VERSION 5.7 ;
  NOWIREEXTENSIONATPIN ON ;
  DIVIDERCHAR "/" ;
  BUSBITCHARS "[]" ;
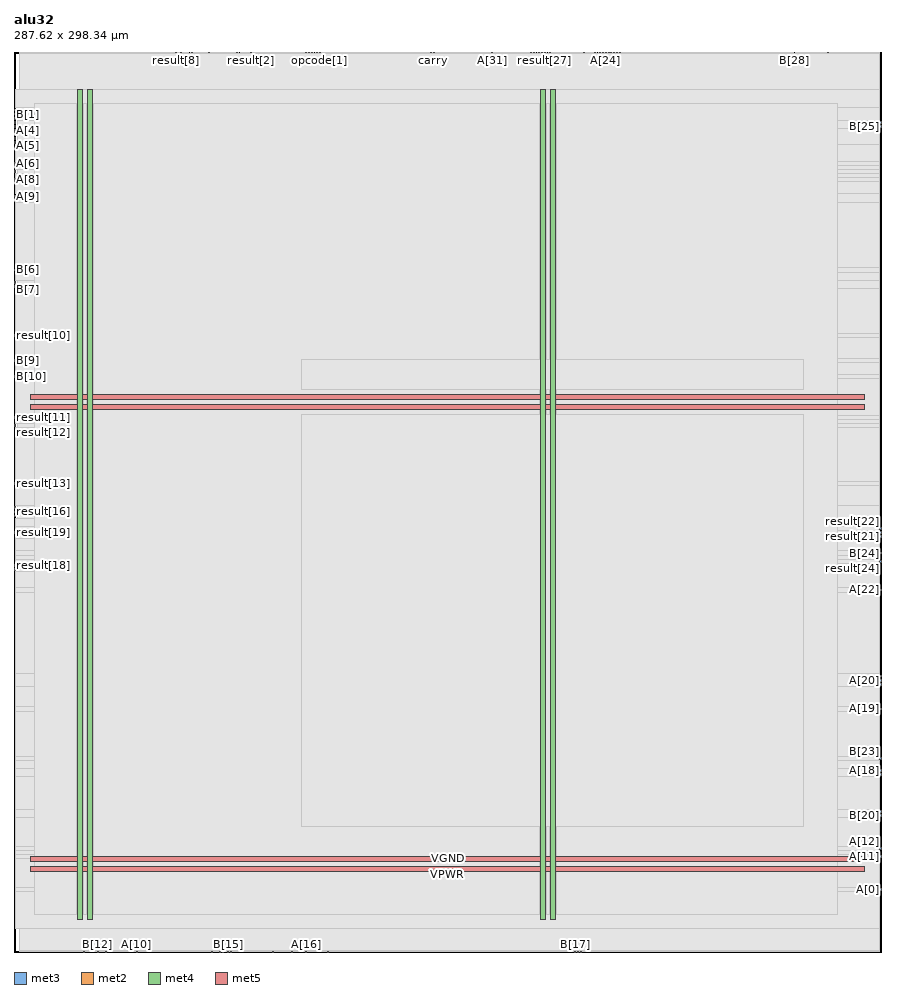
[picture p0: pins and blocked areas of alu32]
MACRO alu32
  CLASS BLOCK ;
  FOREIGN alu32 ;
  ORIGIN 0.000 0.000 ;
  SIZE 287.620 BY 298.340 ;
  PIN A[0]
    DIRECTION INPUT ;
    USE SIGNAL ;
    ANTENNAGATEAREA 0.213000 ;
    PORT
      LAYER met3 ;
        RECT 287.020 20.440 287.620 21.040 ;
    END
  END A[0]
  PIN A[10]
    DIRECTION INPUT ;
    USE SIGNAL ;
    ANTENNAGATEAREA 0.213000 ;
    PORT
      LAYER met2 ;
        RECT 40.570 0.000 40.850 0.280 ;
    END
  END A[10]
  PIN A[11]
    DIRECTION INPUT ;
    USE SIGNAL ;
    ANTENNAGATEAREA 0.247500 ;
    PORT
      LAYER met3 ;
        RECT 287.020 31.320 287.620 31.920 ;
    END
  END A[11]
  PIN A[12]
    DIRECTION INPUT ;
    USE SIGNAL ;
    ANTENNAGATEAREA 0.213000 ;
    PORT
      LAYER met3 ;
        RECT 287.020 34.040 287.620 34.640 ;
    END
  END A[12]
  PIN A[13]
    DIRECTION INPUT ;
    USE SIGNAL ;
    ANTENNAGATEAREA 0.213000 ;
    PORT
      LAYER met2 ;
        RECT 65.410 0.000 65.690 0.280 ;
    END
  END A[13]
  PIN A[14]
    DIRECTION INPUT ;
    USE SIGNAL ;
    ANTENNAGATEAREA 0.159000 ;
    PORT
      LAYER met2 ;
        RECT 68.170 0.000 68.450 0.280 ;
    END
  END A[14]
  PIN A[15]
    DIRECTION INPUT ;
    USE SIGNAL ;
    ANTENNAGATEAREA 0.213000 ;
    PORT
      LAYER met2 ;
        RECT 71.850 0.000 72.130 0.280 ;
    END
  END A[15]
  PIN A[16]
    DIRECTION INPUT ;
    USE SIGNAL ;
    ANTENNAGATEAREA 0.213000 ;
    PORT
      LAYER met2 ;
        RECT 96.690 0.000 96.970 0.280 ;
    END
  END A[16]
  PIN A[17]
    DIRECTION INPUT ;
    USE SIGNAL ;
    ANTENNAGATEAREA 0.196500 ;
    PORT
      LAYER met2 ;
        RECT 85.650 0.000 85.930 0.280 ;
    END
  END A[17]
  PIN A[18]
    DIRECTION INPUT ;
    USE SIGNAL ;
    ANTENNAGATEAREA 0.213000 ;
    PORT
      LAYER met3 ;
        RECT 287.020 59.880 287.620 60.480 ;
    END
  END A[18]
  PIN A[19]
    DIRECTION INPUT ;
    USE SIGNAL ;
    ANTENNAGATEAREA 0.213000 ;
    PORT
      LAYER met3 ;
        RECT 287.020 80.280 287.620 80.880 ;
    END
  END A[19]
  PIN A[1]
    DIRECTION INPUT ;
    USE SIGNAL ;
    ANTENNAGATEAREA 0.495000 ;
    PORT
      LAYER met3 ;
        RECT 0.000 278.840 0.600 279.440 ;
    END
  END A[1]
  PIN A[20]
    DIRECTION INPUT ;
    USE SIGNAL ;
    ANTENNAGATEAREA 0.213000 ;
    PORT
      LAYER met3 ;
        RECT 287.020 89.800 287.620 90.400 ;
    END
  END A[20]
  PIN A[21]
    DIRECTION INPUT ;
    USE SIGNAL ;
    ANTENNAGATEAREA 0.213000 ;
    PORT
      LAYER met3 ;
        RECT 287.020 88.440 287.620 89.040 ;
    END
  END A[21]
  PIN A[22]
    DIRECTION INPUT ;
    USE SIGNAL ;
    ANTENNAGATEAREA 0.213000 ;
    PORT
      LAYER met3 ;
        RECT 287.020 119.720 287.620 120.320 ;
    END
  END A[22]
  PIN A[23]
    DIRECTION INPUT ;
    USE SIGNAL ;
    ANTENNAGATEAREA 0.213000 ;
    PORT
      LAYER met3 ;
        RECT 287.020 91.160 287.620 91.760 ;
    END
  END A[23]
  PIN A[24]
    DIRECTION INPUT ;
    USE SIGNAL ;
    ANTENNAGATEAREA 0.213000 ;
    PORT
      LAYER met2 ;
        RECT 196.050 298.060 196.330 298.340 ;
    END
  END A[24]
  PIN A[25]
    DIRECTION INPUT ;
    USE SIGNAL ;
    ANTENNAGATEAREA 0.213000 ;
    PORT
      LAYER met2 ;
        RECT 195.130 298.060 195.410 298.340 ;
    END
  END A[25]
  PIN A[26]
    DIRECTION INPUT ;
    USE SIGNAL ;
    ANTENNAGATEAREA 0.213000 ;
    PORT
      LAYER met2 ;
        RECT 197.890 298.060 198.170 298.340 ;
    END
  END A[26]
  PIN A[27]
    DIRECTION INPUT ;
    USE SIGNAL ;
    ANTENNAGATEAREA 0.213000 ;
    PORT
      LAYER met2 ;
        RECT 198.810 298.060 199.090 298.340 ;
    END
  END A[27]
  PIN A[28]
    DIRECTION INPUT ;
    USE SIGNAL ;
    ANTENNAGATEAREA 0.213000 ;
    PORT
      LAYER met2 ;
        RECT 199.730 298.060 200.010 298.340 ;
    END
  END A[28]
  PIN A[29]
    DIRECTION INPUT ;
    USE SIGNAL ;
    ANTENNAGATEAREA 0.213000 ;
    PORT
      LAYER met2 ;
        RECT 200.650 298.060 200.930 298.340 ;
    END
  END A[29]
  PIN A[2]
    DIRECTION INPUT ;
    USE SIGNAL ;
    ANTENNAGATEAREA 0.247500 ;
    PORT
      LAYER met3 ;
        RECT 0.000 276.120 0.600 276.720 ;
    END
  END A[2]
  PIN A[30]
    DIRECTION INPUT ;
    USE SIGNAL ;
    ANTENNAGATEAREA 0.196500 ;
    PORT
      LAYER met2 ;
        RECT 196.970 298.060 197.250 298.340 ;
    END
  END A[30]
  PIN A[31]
    DIRECTION INPUT ;
    USE SIGNAL ;
    ANTENNAGATEAREA 0.213000 ;
    PORT
      LAYER met2 ;
        RECT 158.330 298.060 158.610 298.340 ;
    END
  END A[31]
  PIN A[3]
    DIRECTION INPUT ;
    USE SIGNAL ;
    ANTENNAGATEAREA 0.213000 ;
    PORT
      LAYER met3 ;
        RECT 0.000 274.760 0.600 275.360 ;
    END
  END A[3]
  PIN A[4]
    DIRECTION INPUT ;
    USE SIGNAL ;
    ANTENNAGATEAREA 0.213000 ;
    PORT
      LAYER met3 ;
        RECT 0.000 272.040 0.600 272.640 ;
    END
  END A[4]
  PIN A[5]
    DIRECTION INPUT ;
    USE SIGNAL ;
    ANTENNAGATEAREA 0.247500 ;
    PORT
      LAYER met3 ;
        RECT 0.000 269.320 0.600 269.920 ;
    END
  END A[5]
  PIN A[6]
    DIRECTION INPUT ;
    USE SIGNAL ;
    ANTENNAGATEAREA 0.247500 ;
    PORT
      LAYER met3 ;
        RECT 0.000 261.160 0.600 261.760 ;
    END
  END A[6]
  PIN A[7]
    DIRECTION INPUT ;
    USE SIGNAL ;
    ANTENNAGATEAREA 0.213000 ;
    PORT
      LAYER met3 ;
        RECT 0.000 258.440 0.600 259.040 ;
    END
  END A[7]
  PIN A[8]
    DIRECTION INPUT ;
    USE SIGNAL ;
    ANTENNAGATEAREA 0.213000 ;
    PORT
      LAYER met3 ;
        RECT 0.000 255.720 0.600 256.320 ;
    END
  END A[8]
  PIN A[9]
    DIRECTION INPUT ;
    USE SIGNAL ;
    ANTENNAGATEAREA 0.213000 ;
    PORT
      LAYER met3 ;
        RECT 0.000 250.280 0.600 250.880 ;
    END
  END A[9]
  PIN B[0]
    DIRECTION INPUT ;
    USE SIGNAL ;
    ANTENNAGATEAREA 0.126000 ;
    PORT
      LAYER met2 ;
        RECT 194.210 298.060 194.490 298.340 ;
    END
  END B[0]
  PIN B[10]
    DIRECTION INPUT ;
    USE SIGNAL ;
    ANTENNAGATEAREA 0.213000 ;
    PORT
      LAYER met3 ;
        RECT 0.000 190.440 0.600 191.040 ;
    END
  END B[10]
  PIN B[11]
    DIRECTION INPUT ;
    USE SIGNAL ;
    ANTENNAGATEAREA 0.126000 ;
    PORT
      LAYER met2 ;
        RECT 23.090 0.000 23.370 0.280 ;
    END
  END B[11]
  PIN B[12]
    DIRECTION INPUT ;
    USE SIGNAL ;
    ANTENNAGATEAREA 0.247500 ;
    PORT
      LAYER met2 ;
        RECT 27.690 0.000 27.970 0.280 ;
    END
  END B[12]
  PIN B[13]
    DIRECTION INPUT ;
    USE SIGNAL ;
    ANTENNAGATEAREA 0.213000 ;
    PORT
      LAYER met2 ;
        RECT 30.450 0.000 30.730 0.280 ;
    END
  END B[13]
  PIN B[14]
    DIRECTION INPUT ;
    USE SIGNAL ;
    ANTENNAGATEAREA 0.213000 ;
    PORT
      LAYER met2 ;
        RECT 69.090 0.000 69.370 0.280 ;
    END
  END B[14]
  PIN B[15]
    DIRECTION INPUT ;
    USE SIGNAL ;
    ANTENNAGATEAREA 0.213000 ;
    PORT
      LAYER met2 ;
        RECT 70.930 0.000 71.210 0.280 ;
    END
  END B[15]
  PIN B[16]
    DIRECTION INPUT ;
    USE SIGNAL ;
    ANTENNAGATEAREA 0.213000 ;
    PORT
      LAYER met2 ;
        RECT 92.090 0.000 92.370 0.280 ;
    END
  END B[16]
  PIN B[17]
    DIRECTION INPUT ;
    USE SIGNAL ;
    ANTENNAGATEAREA 0.126000 ;
    PORT
      LAYER met2 ;
        RECT 185.930 0.000 186.210 0.280 ;
    END
  END B[17]
  PIN B[18]
    DIRECTION INPUT ;
    USE SIGNAL ;
    ANTENNAGATEAREA 0.126000 ;
    PORT
      LAYER met2 ;
        RECT 186.850 0.000 187.130 0.280 ;
    END
  END B[18]
  PIN B[19]
    DIRECTION INPUT ;
    USE SIGNAL ;
    ANTENNAGATEAREA 0.213000 ;
    PORT
      LAYER met2 ;
        RECT 187.770 0.000 188.050 0.280 ;
    END
  END B[19]
  PIN B[1]
    DIRECTION INPUT ;
    USE SIGNAL ;
    ANTENNAGATEAREA 0.213000 ;
    PORT
      LAYER met3 ;
        RECT 0.000 277.480 0.600 278.080 ;
    END
  END B[1]
  PIN B[20]
    DIRECTION INPUT ;
    USE SIGNAL ;
    ANTENNAGATEAREA 0.126000 ;
    PORT
      LAYER met3 ;
        RECT 287.020 44.920 287.620 45.520 ;
    END
  END B[20]
  PIN B[21]
    DIRECTION INPUT ;
    USE SIGNAL ;
    ANTENNAGATEAREA 0.126000 ;
    PORT
      LAYER met3 ;
        RECT 287.020 46.280 287.620 46.880 ;
    END
  END B[21]
  PIN B[22]
    DIRECTION INPUT ;
    USE SIGNAL ;
    ANTENNAGATEAREA 0.213000 ;
    PORT
      LAYER met3 ;
        RECT 287.020 58.520 287.620 59.120 ;
    END
  END B[22]
  PIN B[23]
    DIRECTION INPUT ;
    USE SIGNAL ;
    ANTENNAGATEAREA 0.213000 ;
    PORT
      LAYER met3 ;
        RECT 287.020 63.960 287.620 64.560 ;
    END
  END B[23]
  PIN B[24]
    DIRECTION INPUT ;
    USE SIGNAL ;
    ANTENNAGATEAREA 0.213000 ;
    PORT
      LAYER met3 ;
        RECT 287.020 131.960 287.620 132.560 ;
    END
  END B[24]
  PIN B[25]
    DIRECTION INPUT ;
    USE SIGNAL ;
    ANTENNAGATEAREA 0.213000 ;
    PORT
      LAYER met3 ;
        RECT 287.020 273.400 287.620 274.000 ;
    END
  END B[25]
  PIN B[26]
    DIRECTION INPUT ;
    USE SIGNAL ;
    ANTENNAGATEAREA 0.213000 ;
    PORT
      LAYER met3 ;
        RECT 287.020 274.760 287.620 275.360 ;
    END
  END B[26]
  PIN B[27]
    DIRECTION INPUT ;
    USE SIGNAL ;
    ANTENNAGATEAREA 0.213000 ;
    PORT
      LAYER met2 ;
        RECT 269.650 298.060 269.930 298.340 ;
    END
  END B[27]
  PIN B[28]
    DIRECTION INPUT ;
    USE SIGNAL ;
    ANTENNAGATEAREA 0.196500 ;
    PORT
      LAYER met2 ;
        RECT 258.610 298.060 258.890 298.340 ;
    END
  END B[28]
  PIN B[29]
    DIRECTION INPUT ;
    USE SIGNAL ;
    ANTENNAGATEAREA 0.213000 ;
    PORT
      LAYER met2 ;
        RECT 193.290 298.060 193.570 298.340 ;
    END
  END B[29]
  PIN B[2]
    DIRECTION INPUT ;
    USE SIGNAL ;
    ANTENNAGATEAREA 0.213000 ;
    PORT
      LAYER met3 ;
        RECT 0.000 273.400 0.600 274.000 ;
    END
  END B[2]
  PIN B[30]
    DIRECTION INPUT ;
    USE SIGNAL ;
    ANTENNAGATEAREA 0.213000 ;
    PORT
      LAYER met2 ;
        RECT 192.370 298.060 192.650 298.340 ;
    END
  END B[30]
  PIN B[31]
    DIRECTION INPUT ;
    USE SIGNAL ;
    ANTENNAGATEAREA 0.213000 ;
    PORT
      LAYER met2 ;
        RECT 188.690 298.060 188.970 298.340 ;
    END
  END B[31]
  PIN B[3]
    DIRECTION INPUT ;
    USE SIGNAL ;
    ANTENNAGATEAREA 0.213000 ;
    PORT
      LAYER met3 ;
        RECT 0.000 270.680 0.600 271.280 ;
    END
  END B[3]
  PIN B[4]
    DIRECTION INPUT ;
    USE SIGNAL ;
    ANTENNAGATEAREA 0.213000 ;
    PORT
      LAYER met3 ;
        RECT 0.000 267.960 0.600 268.560 ;
    END
  END B[4]
  PIN B[5]
    DIRECTION INPUT ;
    USE SIGNAL ;
    ANTENNAGATEAREA 0.159000 ;
    PORT
      LAYER met3 ;
        RECT 0.000 248.920 0.600 249.520 ;
    END
  END B[5]
  PIN B[6]
    DIRECTION INPUT ;
    USE SIGNAL ;
    ANTENNAGATEAREA 0.247500 ;
    PORT
      LAYER met3 ;
        RECT 0.000 225.800 0.600 226.400 ;
    END
  END B[6]
  PIN B[7]
    DIRECTION INPUT ;
    USE SIGNAL ;
    ANTENNAGATEAREA 0.495000 ;
    PORT
      LAYER met3 ;
        RECT 0.000 221.720 0.600 222.320 ;
    END
  END B[7]
  PIN B[8]
    DIRECTION INPUT ;
    USE SIGNAL ;
    ANTENNAGATEAREA 0.159000 ;
    PORT
      LAYER met3 ;
        RECT 0.000 220.360 0.600 220.960 ;
    END
  END B[8]
  PIN B[9]
    DIRECTION INPUT ;
    USE SIGNAL ;
    ANTENNAGATEAREA 0.213000 ;
    PORT
      LAYER met3 ;
        RECT 0.000 195.880 0.600 196.480 ;
    END
  END B[9]
  PIN VGND
    DIRECTION INOUT ;
    USE GROUND ;
    PORT
      LAYER met4 ;
        RECT 24.340 10.640 25.940 285.840 ;
    END
    PORT
      LAYER met4 ;
        RECT 177.940 10.640 179.540 285.840 ;
    END
    PORT
      LAYER met5 ;
        RECT 5.520 30.030 281.980 31.630 ;
    END
    PORT
      LAYER met5 ;
        RECT 5.520 183.210 281.980 184.810 ;
    END
  END VGND
  PIN VPWR
    DIRECTION INOUT ;
    USE POWER ;
    PORT
      LAYER met4 ;
        RECT 21.040 10.640 22.640 285.840 ;
    END
    PORT
      LAYER met4 ;
        RECT 174.640 10.640 176.240 285.840 ;
    END
    PORT
      LAYER met5 ;
        RECT 5.520 26.730 281.980 28.330 ;
    END
    PORT
      LAYER met5 ;
        RECT 5.520 179.910 281.980 181.510 ;
    END
  END VPWR
  PIN carry
    DIRECTION OUTPUT ;
    USE SIGNAL ;
    ANTENNAGATEAREA 0.126000 ;
    ANTENNADIFFAREA 0.429000 ;
    PORT
      LAYER met2 ;
        RECT 139.010 298.060 139.290 298.340 ;
    END
  END carry
  PIN opcode[0]
    DIRECTION INPUT ;
    USE SIGNAL ;
    ANTENNAGATEAREA 0.213000 ;
    PORT
      LAYER met2 ;
        RECT 98.530 298.060 98.810 298.340 ;
    END
  END opcode[0]
  PIN opcode[1]
    DIRECTION INPUT ;
    USE SIGNAL ;
    ANTENNAGATEAREA 0.213000 ;
    PORT
      LAYER met2 ;
        RECT 101.290 298.060 101.570 298.340 ;
    END
  END opcode[1]
  PIN opcode[2]
    DIRECTION INPUT ;
    USE SIGNAL ;
    ANTENNAGATEAREA 0.213000 ;
    PORT
      LAYER met2 ;
        RECT 99.450 298.060 99.730 298.340 ;
    END
  END opcode[2]
  PIN opcode[3]
    DIRECTION INPUT ;
    USE SIGNAL ;
    ANTENNAGATEAREA 0.213000 ;
    PORT
      LAYER met2 ;
        RECT 100.370 298.060 100.650 298.340 ;
    END
  END opcode[3]
  PIN overflow
    DIRECTION OUTPUT ;
    USE SIGNAL ;
    ANTENNADIFFAREA 1.782000 ;
    PORT
      LAYER met2 ;
        RECT 138.090 298.060 138.370 298.340 ;
    END
  END overflow
  PIN result[0]
    DIRECTION OUTPUT ;
    USE SIGNAL ;
    ANTENNAGATEAREA 0.126000 ;
    ANTENNADIFFAREA 0.429000 ;
    PORT
      LAYER met2 ;
        RECT 97.610 298.060 97.890 298.340 ;
    END
  END result[0]
  PIN result[10]
    DIRECTION OUTPUT ;
    USE SIGNAL ;
    ANTENNADIFFAREA 0.383400 ;
    PORT
      LAYER met3 ;
        RECT 0.000 204.040 0.600 204.640 ;
    END
  END result[10]
  PIN result[11]
    DIRECTION OUTPUT ;
    USE SIGNAL ;
    ANTENNADIFFAREA 0.383400 ;
    PORT
      LAYER met3 ;
        RECT 0.000 176.840 0.600 177.440 ;
    END
  END result[11]
  PIN result[12]
    DIRECTION OUTPUT ;
    USE SIGNAL ;
    ANTENNAGATEAREA 0.126000 ;
    ANTENNADIFFAREA 0.429000 ;
    PORT
      LAYER met3 ;
        RECT 0.000 174.120 0.600 174.720 ;
    END
  END result[12]
  PIN result[13]
    DIRECTION OUTPUT ;
    USE SIGNAL ;
    ANTENNAGATEAREA 0.126000 ;
    ANTENNADIFFAREA 0.429000 ;
    PORT
      LAYER met3 ;
        RECT 0.000 155.080 0.600 155.680 ;
    END
  END result[13]
  PIN result[14]
    DIRECTION OUTPUT ;
    USE SIGNAL ;
    ANTENNADIFFAREA 0.383400 ;
    PORT
      LAYER met3 ;
        RECT 0.000 146.920 0.600 147.520 ;
    END
  END result[14]
  PIN result[15]
    DIRECTION OUTPUT ;
    USE SIGNAL ;
    ANTENNADIFFAREA 0.383400 ;
    PORT
      LAYER met3 ;
        RECT 0.000 144.200 0.600 144.800 ;
    END
  END result[15]
  PIN result[16]
    DIRECTION OUTPUT ;
    USE SIGNAL ;
    ANTENNAGATEAREA 0.126000 ;
    ANTENNADIFFAREA 0.429000 ;
    PORT
      LAYER met3 ;
        RECT 0.000 145.560 0.600 146.160 ;
    END
  END result[16]
  PIN result[17]
    DIRECTION OUTPUT ;
    USE SIGNAL ;
    ANTENNAGATEAREA 0.126000 ;
    ANTENNADIFFAREA 0.429000 ;
    PORT
      LAYER met2 ;
        RECT 104.050 0.000 104.330 0.280 ;
    END
  END result[17]
  PIN result[18]
    DIRECTION OUTPUT ;
    USE SIGNAL ;
    ANTENNAGATEAREA 0.126000 ;
    ANTENNADIFFAREA 0.429000 ;
    PORT
      LAYER met3 ;
        RECT 0.000 127.880 0.600 128.480 ;
    END
  END result[18]
  PIN result[19]
    DIRECTION OUTPUT ;
    USE SIGNAL ;
    ANTENNADIFFAREA 0.383400 ;
    PORT
      LAYER met3 ;
        RECT 0.000 138.760 0.600 139.360 ;
    END
  END result[19]
  PIN result[1]
    DIRECTION OUTPUT ;
    USE SIGNAL ;
    ANTENNADIFFAREA 0.702900 ;
    PORT
      LAYER met2 ;
        RECT 96.690 298.060 96.970 298.340 ;
    END
  END result[1]
  PIN result[20]
    DIRECTION OUTPUT ;
    USE SIGNAL ;
    ANTENNADIFFAREA 0.891000 ;
    PORT
      LAYER met3 ;
        RECT 0.000 126.520 0.600 127.120 ;
    END
  END result[20]
  PIN result[21]
    DIRECTION OUTPUT ;
    USE SIGNAL ;
    ANTENNADIFFAREA 0.383400 ;
    PORT
      LAYER met3 ;
        RECT 287.020 137.400 287.620 138.000 ;
    END
  END result[21]
  PIN result[22]
    DIRECTION OUTPUT ;
    USE SIGNAL ;
    ANTENNADIFFAREA 1.782000 ;
    PORT
      LAYER met3 ;
        RECT 287.020 140.120 287.620 140.720 ;
    END
  END result[22]
  PIN result[23]
    DIRECTION OUTPUT ;
    USE SIGNAL ;
    ANTENNAGATEAREA 0.126000 ;
    ANTENNADIFFAREA 0.429000 ;
    PORT
      LAYER met3 ;
        RECT 287.020 138.760 287.620 139.360 ;
    END
  END result[23]
  PIN result[24]
    DIRECTION OUTPUT ;
    USE SIGNAL ;
    ANTENNAGATEAREA 0.126000 ;
    ANTENNADIFFAREA 0.429000 ;
    PORT
      LAYER met3 ;
        RECT 287.020 129.240 287.620 129.840 ;
    END
  END result[24]
  PIN result[25]
    DIRECTION OUTPUT ;
    USE SIGNAL ;
    ANTENNADIFFAREA 1.336500 ;
    PORT
      LAYER met2 ;
        RECT 171.210 298.060 171.490 298.340 ;
    END
  END result[25]
  PIN result[26]
    DIRECTION OUTPUT ;
    USE SIGNAL ;
    ANTENNADIFFAREA 1.336500 ;
    PORT
      LAYER met2 ;
        RECT 173.050 298.060 173.330 298.340 ;
    END
  END result[26]
  PIN result[27]
    DIRECTION OUTPUT ;
    USE SIGNAL ;
    ANTENNADIFFAREA 0.795200 ;
    PORT
      LAYER met2 ;
        RECT 175.810 298.060 176.090 298.340 ;
    END
  END result[27]
  PIN result[28]
    DIRECTION OUTPUT ;
    USE SIGNAL ;
    ANTENNADIFFAREA 1.782000 ;
    PORT
      LAYER met2 ;
        RECT 173.970 298.060 174.250 298.340 ;
    END
  END result[28]
  PIN result[29]
    DIRECTION OUTPUT ;
    USE SIGNAL ;
    ANTENNADIFFAREA 1.782000 ;
    PORT
      LAYER met2 ;
        RECT 177.650 298.060 177.930 298.340 ;
    END
  END result[29]
  PIN result[2]
    DIRECTION OUTPUT ;
    USE SIGNAL ;
    ANTENNADIFFAREA 0.702900 ;
    PORT
      LAYER met2 ;
        RECT 78.290 298.060 78.570 298.340 ;
    END
  END result[2]
  PIN result[30]
    DIRECTION OUTPUT ;
    USE SIGNAL ;
    ANTENNADIFFAREA 1.336500 ;
    PORT
      LAYER met2 ;
        RECT 174.890 298.060 175.170 298.340 ;
    END
  END result[30]
  PIN result[31]
    DIRECTION OUTPUT ;
    USE SIGNAL ;
    ANTENNADIFFAREA 1.782000 ;
    PORT
      LAYER met2 ;
        RECT 172.130 298.060 172.410 298.340 ;
    END
  END result[31]
  PIN result[3]
    DIRECTION OUTPUT ;
    USE SIGNAL ;
    ANTENNAGATEAREA 0.126000 ;
    ANTENNADIFFAREA 0.429000 ;
    PORT
      LAYER met2 ;
        RECT 74.610 298.060 74.890 298.340 ;
    END
  END result[3]
  PIN result[4]
    DIRECTION OUTPUT ;
    USE SIGNAL ;
    ANTENNADIFFAREA 0.383400 ;
    PORT
      LAYER met2 ;
        RECT 73.690 298.060 73.970 298.340 ;
    END
  END result[4]
  PIN result[5]
    DIRECTION OUTPUT ;
    USE SIGNAL ;
    ANTENNADIFFAREA 0.383400 ;
    PORT
      LAYER met2 ;
        RECT 64.490 298.060 64.770 298.340 ;
    END
  END result[5]
  PIN result[6]
    DIRECTION OUTPUT ;
    USE SIGNAL ;
    ANTENNAGATEAREA 0.126000 ;
    ANTENNADIFFAREA 0.429000 ;
    PORT
      LAYER met2 ;
        RECT 58.050 298.060 58.330 298.340 ;
    END
  END result[6]
  PIN result[7]
    DIRECTION OUTPUT ;
    USE SIGNAL ;
    ANTENNADIFFAREA 0.383400 ;
    PORT
      LAYER met2 ;
        RECT 58.970 298.060 59.250 298.340 ;
    END
  END result[7]
  PIN result[8]
    DIRECTION OUTPUT ;
    USE SIGNAL ;
    ANTENNADIFFAREA 0.383400 ;
    PORT
      LAYER met2 ;
        RECT 53.450 298.060 53.730 298.340 ;
    END
  END result[8]
  PIN result[9]
    DIRECTION OUTPUT ;
    USE SIGNAL ;
    ANTENNADIFFAREA 0.383400 ;
    PORT
      LAYER met2 ;
        RECT 55.290 298.060 55.570 298.340 ;
    END
  END result[9]
  PIN zero
    DIRECTION OUTPUT ;
    USE SIGNAL ;
    ANTENNADIFFAREA 1.336500 ;
    PORT
      LAYER met2 ;
        RECT 176.730 298.060 177.010 298.340 ;
    END
  END zero
  OBS
      LAYER nwell ;
        RECT 5.330 10.795 282.170 285.790 ;
      LAYER li1 ;
        RECT 5.520 10.795 281.980 285.685 ;
      LAYER met1 ;
        RECT 1.910 10.640 286.970 286.920 ;
      LAYER met2 ;
        RECT 1.930 297.780 53.170 298.060 ;
        RECT 54.010 297.780 55.010 298.060 ;
        RECT 55.850 297.780 57.770 298.060 ;
        RECT 58.610 297.780 58.690 298.060 ;
        RECT 59.530 297.780 64.210 298.060 ;
        RECT 65.050 297.780 73.410 298.060 ;
        RECT 74.250 297.780 74.330 298.060 ;
        RECT 75.170 297.780 78.010 298.060 ;
        RECT 78.850 297.780 96.410 298.060 ;
        RECT 97.250 297.780 97.330 298.060 ;
        RECT 98.170 297.780 98.250 298.060 ;
        RECT 99.090 297.780 99.170 298.060 ;
        RECT 100.010 297.780 100.090 298.060 ;
        RECT 100.930 297.780 101.010 298.060 ;
        RECT 101.850 297.780 137.810 298.060 ;
        RECT 138.650 297.780 138.730 298.060 ;
        RECT 139.570 297.780 158.050 298.060 ;
        RECT 158.890 297.780 170.930 298.060 ;
        RECT 171.770 297.780 171.850 298.060 ;
        RECT 172.690 297.780 172.770 298.060 ;
        RECT 173.610 297.780 173.690 298.060 ;
        RECT 174.530 297.780 174.610 298.060 ;
        RECT 175.450 297.780 175.530 298.060 ;
        RECT 176.370 297.780 176.450 298.060 ;
        RECT 177.290 297.780 177.370 298.060 ;
        RECT 178.210 297.780 188.410 298.060 ;
        RECT 189.250 297.780 192.090 298.060 ;
        RECT 192.930 297.780 193.010 298.060 ;
        RECT 193.850 297.780 193.930 298.060 ;
        RECT 194.770 297.780 194.850 298.060 ;
        RECT 195.690 297.780 195.770 298.060 ;
        RECT 196.610 297.780 196.690 298.060 ;
        RECT 197.530 297.780 197.610 298.060 ;
        RECT 198.450 297.780 198.530 298.060 ;
        RECT 199.370 297.780 199.450 298.060 ;
        RECT 200.290 297.780 200.370 298.060 ;
        RECT 201.210 297.780 258.330 298.060 ;
        RECT 259.170 297.780 269.370 298.060 ;
        RECT 270.210 297.780 286.940 298.060 ;
        RECT 1.930 0.560 286.940 297.780 ;
        RECT 1.930 0.280 22.810 0.560 ;
        RECT 23.650 0.280 27.410 0.560 ;
        RECT 28.250 0.280 30.170 0.560 ;
        RECT 31.010 0.280 40.290 0.560 ;
        RECT 41.130 0.280 65.130 0.560 ;
        RECT 65.970 0.280 67.890 0.560 ;
        RECT 68.730 0.280 68.810 0.560 ;
        RECT 69.650 0.280 70.650 0.560 ;
        RECT 71.490 0.280 71.570 0.560 ;
        RECT 72.410 0.280 85.370 0.560 ;
        RECT 86.210 0.280 91.810 0.560 ;
        RECT 92.650 0.280 96.410 0.560 ;
        RECT 97.250 0.280 103.770 0.560 ;
        RECT 104.610 0.280 185.650 0.560 ;
        RECT 186.490 0.280 186.570 0.560 ;
        RECT 187.410 0.280 187.490 0.560 ;
        RECT 188.330 0.280 286.940 0.560 ;
      LAYER met3 ;
        RECT 0.600 279.840 287.020 285.765 ;
        RECT 1.000 275.760 287.020 279.840 ;
        RECT 1.000 273.000 286.620 275.760 ;
        RECT 1.000 267.560 287.020 273.000 ;
        RECT 0.600 262.160 287.020 267.560 ;
        RECT 1.000 260.760 287.020 262.160 ;
        RECT 0.600 259.440 287.020 260.760 ;
        RECT 1.000 258.040 287.020 259.440 ;
        RECT 0.600 256.720 287.020 258.040 ;
        RECT 1.000 255.320 287.020 256.720 ;
        RECT 0.600 251.280 287.020 255.320 ;
        RECT 1.000 248.520 287.020 251.280 ;
        RECT 0.600 226.800 287.020 248.520 ;
        RECT 1.000 225.400 287.020 226.800 ;
        RECT 0.600 222.720 287.020 225.400 ;
        RECT 1.000 219.960 287.020 222.720 ;
        RECT 0.600 205.040 287.020 219.960 ;
        RECT 1.000 203.640 287.020 205.040 ;
        RECT 0.600 196.880 287.020 203.640 ;
        RECT 1.000 195.480 287.020 196.880 ;
        RECT 0.600 191.440 287.020 195.480 ;
        RECT 1.000 190.040 287.020 191.440 ;
        RECT 0.600 177.840 287.020 190.040 ;
        RECT 1.000 176.440 287.020 177.840 ;
        RECT 0.600 175.120 287.020 176.440 ;
        RECT 1.000 173.720 287.020 175.120 ;
        RECT 0.600 156.080 287.020 173.720 ;
        RECT 1.000 154.680 287.020 156.080 ;
        RECT 0.600 147.920 287.020 154.680 ;
        RECT 1.000 143.800 287.020 147.920 ;
        RECT 0.600 141.120 287.020 143.800 ;
        RECT 0.600 139.760 286.620 141.120 ;
        RECT 1.000 138.360 286.620 139.760 ;
        RECT 0.600 137.000 286.620 138.360 ;
        RECT 0.600 132.960 287.020 137.000 ;
        RECT 0.600 131.560 286.620 132.960 ;
        RECT 0.600 130.240 287.020 131.560 ;
        RECT 0.600 128.880 286.620 130.240 ;
        RECT 1.000 128.840 286.620 128.880 ;
        RECT 1.000 126.120 287.020 128.840 ;
        RECT 0.600 120.720 287.020 126.120 ;
        RECT 0.600 119.320 286.620 120.720 ;
        RECT 0.600 92.160 287.020 119.320 ;
        RECT 0.600 88.040 286.620 92.160 ;
        RECT 0.600 81.280 287.020 88.040 ;
        RECT 0.600 79.880 286.620 81.280 ;
        RECT 0.600 64.960 287.020 79.880 ;
        RECT 0.600 63.560 286.620 64.960 ;
        RECT 0.600 60.880 287.020 63.560 ;
        RECT 0.600 58.120 286.620 60.880 ;
        RECT 0.600 47.280 287.020 58.120 ;
        RECT 0.600 44.520 286.620 47.280 ;
        RECT 0.600 35.040 287.020 44.520 ;
        RECT 0.600 33.640 286.620 35.040 ;
        RECT 0.600 32.320 287.020 33.640 ;
        RECT 0.600 30.920 286.620 32.320 ;
        RECT 0.600 21.440 287.020 30.920 ;
        RECT 0.600 20.040 286.620 21.440 ;
        RECT 0.600 7.655 287.020 20.040 ;
      LAYER met4 ;
        RECT 6.735 12.415 20.640 281.345 ;
        RECT 23.040 12.415 23.940 281.345 ;
        RECT 26.340 12.415 174.240 281.345 ;
        RECT 176.640 12.415 177.540 281.345 ;
        RECT 179.940 12.415 272.945 281.345 ;
      LAYER met5 ;
        RECT 95.340 186.410 261.620 196.300 ;
        RECT 95.340 41.700 261.620 178.310 ;
  END
END alu32
END LIBRARY

